# Generated by FakeRAM 2.0
VERSION 5.7 ;
BUSBITCHARS "[]" ;
PROPERTYDEFINITIONS
  MACRO width INTEGER ;
  MACRO depth INTEGER ;
  MACRO banks INTEGER ;
END PROPERTYDEFINITIONS
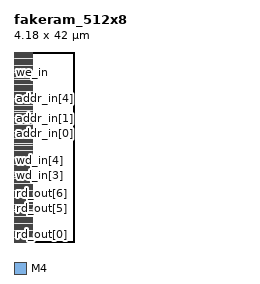
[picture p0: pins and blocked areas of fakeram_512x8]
MACRO fakeram_512x8
  PROPERTY width 8 ;
  PROPERTY depth 512 ;
  PROPERTY banks 4 ;
  FOREIGN fakeram_512x8 0 0 ;
  SYMMETRY X Y R90 ;
  SIZE 4.180 BY 42.000 ;
  CLASS BLOCK ;
  PIN rd_out[0]
    DIRECTION OUTPUT ;
    USE SIGNAL ;
    SHAPE ABUTMENT ;
    PORT
      LAYER M4 ;
      RECT 0.000 0.048 0.024 0.072 ;
    END
  END rd_out[0]
  PIN rd_out[1]
    DIRECTION OUTPUT ;
    USE SIGNAL ;
    SHAPE ABUTMENT ;
    PORT
      LAYER M4 ;
      RECT 0.000 1.536 0.024 1.560 ;
    END
  END rd_out[1]
  PIN rd_out[2]
    DIRECTION OUTPUT ;
    USE SIGNAL ;
    SHAPE ABUTMENT ;
    PORT
      LAYER M4 ;
      RECT 0.000 3.024 0.024 3.048 ;
    END
  END rd_out[2]
  PIN rd_out[3]
    DIRECTION OUTPUT ;
    USE SIGNAL ;
    SHAPE ABUTMENT ;
    PORT
      LAYER M4 ;
      RECT 0.000 4.512 0.024 4.536 ;
    END
  END rd_out[3]
  PIN rd_out[4]
    DIRECTION OUTPUT ;
    USE SIGNAL ;
    SHAPE ABUTMENT ;
    PORT
      LAYER M4 ;
      RECT 0.000 6.000 0.024 6.024 ;
    END
  END rd_out[4]
  PIN rd_out[5]
    DIRECTION OUTPUT ;
    USE SIGNAL ;
    SHAPE ABUTMENT ;
    PORT
      LAYER M4 ;
      RECT 0.000 7.488 0.024 7.512 ;
    END
  END rd_out[5]
  PIN rd_out[6]
    DIRECTION OUTPUT ;
    USE SIGNAL ;
    SHAPE ABUTMENT ;
    PORT
      LAYER M4 ;
      RECT 0.000 8.976 0.024 9.000 ;
    END
  END rd_out[6]
  PIN rd_out[7]
    DIRECTION OUTPUT ;
    USE SIGNAL ;
    SHAPE ABUTMENT ;
    PORT
      LAYER M4 ;
      RECT 0.000 10.464 0.024 10.488 ;
    END
  END rd_out[7]
  PIN wd_in[0]
    DIRECTION INPUT ;
    USE SIGNAL ;
    SHAPE ABUTMENT ;
    PORT
      LAYER M4 ;
      RECT 0.000 12.000 0.024 12.024 ;
    END
  END wd_in[0]
  PIN wd_in[1]
    DIRECTION INPUT ;
    USE SIGNAL ;
    SHAPE ABUTMENT ;
    PORT
      LAYER M4 ;
      RECT 0.000 13.488 0.024 13.512 ;
    END
  END wd_in[1]
  PIN wd_in[2]
    DIRECTION INPUT ;
    USE SIGNAL ;
    SHAPE ABUTMENT ;
    PORT
      LAYER M4 ;
      RECT 0.000 14.976 0.024 15.000 ;
    END
  END wd_in[2]
  PIN wd_in[3]
    DIRECTION INPUT ;
    USE SIGNAL ;
    SHAPE ABUTMENT ;
    PORT
      LAYER M4 ;
      RECT 0.000 16.464 0.024 16.488 ;
    END
  END wd_in[3]
  PIN wd_in[4]
    DIRECTION INPUT ;
    USE SIGNAL ;
    SHAPE ABUTMENT ;
    PORT
      LAYER M4 ;
      RECT 0.000 17.952 0.024 17.976 ;
    END
  END wd_in[4]
  PIN wd_in[5]
    DIRECTION INPUT ;
    USE SIGNAL ;
    SHAPE ABUTMENT ;
    PORT
      LAYER M4 ;
      RECT 0.000 19.440 0.024 19.464 ;
    END
  END wd_in[5]
  PIN wd_in[6]
    DIRECTION INPUT ;
    USE SIGNAL ;
    SHAPE ABUTMENT ;
    PORT
      LAYER M4 ;
      RECT 0.000 20.928 0.024 20.952 ;
    END
  END wd_in[6]
  PIN wd_in[7]
    DIRECTION INPUT ;
    USE SIGNAL ;
    SHAPE ABUTMENT ;
    PORT
      LAYER M4 ;
      RECT 0.000 22.416 0.024 22.440 ;
    END
  END wd_in[7]
  PIN addr_in[0]
    DIRECTION INPUT ;
    USE SIGNAL ;
    SHAPE ABUTMENT ;
    PORT
      LAYER M4 ;
      RECT 0.000 23.952 0.024 23.976 ;
    END
  END addr_in[0]
  PIN addr_in[1]
    DIRECTION INPUT ;
    USE SIGNAL ;
    SHAPE ABUTMENT ;
    PORT
      LAYER M4 ;
      RECT 0.000 25.440 0.024 25.464 ;
    END
  END addr_in[1]
  PIN addr_in[2]
    DIRECTION INPUT ;
    USE SIGNAL ;
    SHAPE ABUTMENT ;
    PORT
      LAYER M4 ;
      RECT 0.000 26.928 0.024 26.952 ;
    END
  END addr_in[2]
  PIN addr_in[3]
    DIRECTION INPUT ;
    USE SIGNAL ;
    SHAPE ABUTMENT ;
    PORT
      LAYER M4 ;
      RECT 0.000 28.416 0.024 28.440 ;
    END
  END addr_in[3]
  PIN addr_in[4]
    DIRECTION INPUT ;
    USE SIGNAL ;
    SHAPE ABUTMENT ;
    PORT
      LAYER M4 ;
      RECT 0.000 29.904 0.024 29.928 ;
    END
  END addr_in[4]
  PIN addr_in[5]
    DIRECTION INPUT ;
    USE SIGNAL ;
    SHAPE ABUTMENT ;
    PORT
      LAYER M4 ;
      RECT 0.000 31.392 0.024 31.416 ;
    END
  END addr_in[5]
  PIN addr_in[6]
    DIRECTION INPUT ;
    USE SIGNAL ;
    SHAPE ABUTMENT ;
    PORT
      LAYER M4 ;
      RECT 0.000 32.880 0.024 32.904 ;
    END
  END addr_in[6]
  PIN addr_in[7]
    DIRECTION INPUT ;
    USE SIGNAL ;
    SHAPE ABUTMENT ;
    PORT
      LAYER M4 ;
      RECT 0.000 34.368 0.024 34.392 ;
    END
  END addr_in[7]
  PIN addr_in[8]
    DIRECTION INPUT ;
    USE SIGNAL ;
    SHAPE ABUTMENT ;
    PORT
      LAYER M4 ;
      RECT 0.000 35.856 0.024 35.880 ;
    END
  END addr_in[8]
  PIN we_in
    DIRECTION INPUT ;
    USE SIGNAL ;
    SHAPE ABUTMENT ;
    PORT
      LAYER M4 ;
      RECT 0.000 37.392 0.024 37.416 ;
    END
  END we_in
  PIN ce_in
    DIRECTION INPUT ;
    USE SIGNAL ;
    SHAPE ABUTMENT ;
    PORT
      LAYER M4 ;
      RECT 0.000 38.880 0.024 38.904 ;
    END
  END ce_in
  PIN clk
    DIRECTION INPUT ;
    USE SIGNAL ;
    SHAPE ABUTMENT ;
    PORT
      LAYER M4 ;
      RECT 0.000 40.368 0.024 40.392 ;
    END
  END clk
  PIN VSS
    DIRECTION INOUT ;
    USE GROUND ;
    PORT
      LAYER M4 ;
      RECT 0.048 0.000 4.132 0.096 ;
      RECT 0.048 0.768 4.132 0.864 ;
      RECT 0.048 1.536 4.132 1.632 ;
      RECT 0.048 2.304 4.132 2.400 ;
      RECT 0.048 3.072 4.132 3.168 ;
      RECT 0.048 3.840 4.132 3.936 ;
      RECT 0.048 4.608 4.132 4.704 ;
      RECT 0.048 5.376 4.132 5.472 ;
      RECT 0.048 6.144 4.132 6.240 ;
      RECT 0.048 6.912 4.132 7.008 ;
      RECT 0.048 7.680 4.132 7.776 ;
      RECT 0.048 8.448 4.132 8.544 ;
      RECT 0.048 9.216 4.132 9.312 ;
      RECT 0.048 9.984 4.132 10.080 ;
      RECT 0.048 10.752 4.132 10.848 ;
      RECT 0.048 11.520 4.132 11.616 ;
      RECT 0.048 12.288 4.132 12.384 ;
      RECT 0.048 13.056 4.132 13.152 ;
      RECT 0.048 13.824 4.132 13.920 ;
      RECT 0.048 14.592 4.132 14.688 ;
      RECT 0.048 15.360 4.132 15.456 ;
      RECT 0.048 16.128 4.132 16.224 ;
      RECT 0.048 16.896 4.132 16.992 ;
      RECT 0.048 17.664 4.132 17.760 ;
      RECT 0.048 18.432 4.132 18.528 ;
      RECT 0.048 19.200 4.132 19.296 ;
      RECT 0.048 19.968 4.132 20.064 ;
      RECT 0.048 20.736 4.132 20.832 ;
      RECT 0.048 21.504 4.132 21.600 ;
      RECT 0.048 22.272 4.132 22.368 ;
      RECT 0.048 23.040 4.132 23.136 ;
      RECT 0.048 23.808 4.132 23.904 ;
      RECT 0.048 24.576 4.132 24.672 ;
      RECT 0.048 25.344 4.132 25.440 ;
      RECT 0.048 26.112 4.132 26.208 ;
      RECT 0.048 26.880 4.132 26.976 ;
      RECT 0.048 27.648 4.132 27.744 ;
      RECT 0.048 28.416 4.132 28.512 ;
      RECT 0.048 29.184 4.132 29.280 ;
      RECT 0.048 29.952 4.132 30.048 ;
      RECT 0.048 30.720 4.132 30.816 ;
      RECT 0.048 31.488 4.132 31.584 ;
      RECT 0.048 32.256 4.132 32.352 ;
      RECT 0.048 33.024 4.132 33.120 ;
      RECT 0.048 33.792 4.132 33.888 ;
      RECT 0.048 34.560 4.132 34.656 ;
      RECT 0.048 35.328 4.132 35.424 ;
      RECT 0.048 36.096 4.132 36.192 ;
      RECT 0.048 36.864 4.132 36.960 ;
      RECT 0.048 37.632 4.132 37.728 ;
      RECT 0.048 38.400 4.132 38.496 ;
      RECT 0.048 39.168 4.132 39.264 ;
      RECT 0.048 39.936 4.132 40.032 ;
      RECT 0.048 40.704 4.132 40.800 ;
      RECT 0.048 41.472 4.132 41.568 ;
    END
  END VSS
  PIN VDD
    DIRECTION INOUT ;
    USE POWER ;
    PORT
      LAYER M4 ;
      RECT 0.048 0.384 4.132 0.480 ;
      RECT 0.048 1.152 4.132 1.248 ;
      RECT 0.048 1.920 4.132 2.016 ;
      RECT 0.048 2.688 4.132 2.784 ;
      RECT 0.048 3.456 4.132 3.552 ;
      RECT 0.048 4.224 4.132 4.320 ;
      RECT 0.048 4.992 4.132 5.088 ;
      RECT 0.048 5.760 4.132 5.856 ;
      RECT 0.048 6.528 4.132 6.624 ;
      RECT 0.048 7.296 4.132 7.392 ;
      RECT 0.048 8.064 4.132 8.160 ;
      RECT 0.048 8.832 4.132 8.928 ;
      RECT 0.048 9.600 4.132 9.696 ;
      RECT 0.048 10.368 4.132 10.464 ;
      RECT 0.048 11.136 4.132 11.232 ;
      RECT 0.048 11.904 4.132 12.000 ;
      RECT 0.048 12.672 4.132 12.768 ;
      RECT 0.048 13.440 4.132 13.536 ;
      RECT 0.048 14.208 4.132 14.304 ;
      RECT 0.048 14.976 4.132 15.072 ;
      RECT 0.048 15.744 4.132 15.840 ;
      RECT 0.048 16.512 4.132 16.608 ;
      RECT 0.048 17.280 4.132 17.376 ;
      RECT 0.048 18.048 4.132 18.144 ;
      RECT 0.048 18.816 4.132 18.912 ;
      RECT 0.048 19.584 4.132 19.680 ;
      RECT 0.048 20.352 4.132 20.448 ;
      RECT 0.048 21.120 4.132 21.216 ;
      RECT 0.048 21.888 4.132 21.984 ;
      RECT 0.048 22.656 4.132 22.752 ;
      RECT 0.048 23.424 4.132 23.520 ;
      RECT 0.048 24.192 4.132 24.288 ;
      RECT 0.048 24.960 4.132 25.056 ;
      RECT 0.048 25.728 4.132 25.824 ;
      RECT 0.048 26.496 4.132 26.592 ;
      RECT 0.048 27.264 4.132 27.360 ;
      RECT 0.048 28.032 4.132 28.128 ;
      RECT 0.048 28.800 4.132 28.896 ;
      RECT 0.048 29.568 4.132 29.664 ;
      RECT 0.048 30.336 4.132 30.432 ;
      RECT 0.048 31.104 4.132 31.200 ;
      RECT 0.048 31.872 4.132 31.968 ;
      RECT 0.048 32.640 4.132 32.736 ;
      RECT 0.048 33.408 4.132 33.504 ;
      RECT 0.048 34.176 4.132 34.272 ;
      RECT 0.048 34.944 4.132 35.040 ;
      RECT 0.048 35.712 4.132 35.808 ;
      RECT 0.048 36.480 4.132 36.576 ;
      RECT 0.048 37.248 4.132 37.344 ;
      RECT 0.048 38.016 4.132 38.112 ;
      RECT 0.048 38.784 4.132 38.880 ;
      RECT 0.048 39.552 4.132 39.648 ;
      RECT 0.048 40.320 4.132 40.416 ;
      RECT 0.048 41.088 4.132 41.184 ;
      RECT 0.048 41.856 4.132 41.952 ;
    END
  END VDD
  OBS
    LAYER M1 ;
    RECT 0 0 4.180 42.000 ;
    LAYER M2 ;
    RECT 0 0 4.180 42.000 ;
    LAYER M3 ;
    RECT 0 0 4.180 42.000 ;
    LAYER M4 ;
    RECT 0 0 4.180 42.000 ;
  END
END fakeram_512x8

END LIBRARY
